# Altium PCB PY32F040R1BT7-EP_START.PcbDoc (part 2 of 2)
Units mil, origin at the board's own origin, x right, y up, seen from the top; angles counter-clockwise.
Board outline 1771.65 x 3925.12 mil, 2 copper layers (Top Layer, Bottom Layer), stack 21 mil thick; 157 components, 167 nets, 618 pads, 288 vias.
Unrouted connection lines stored in the file: 5.

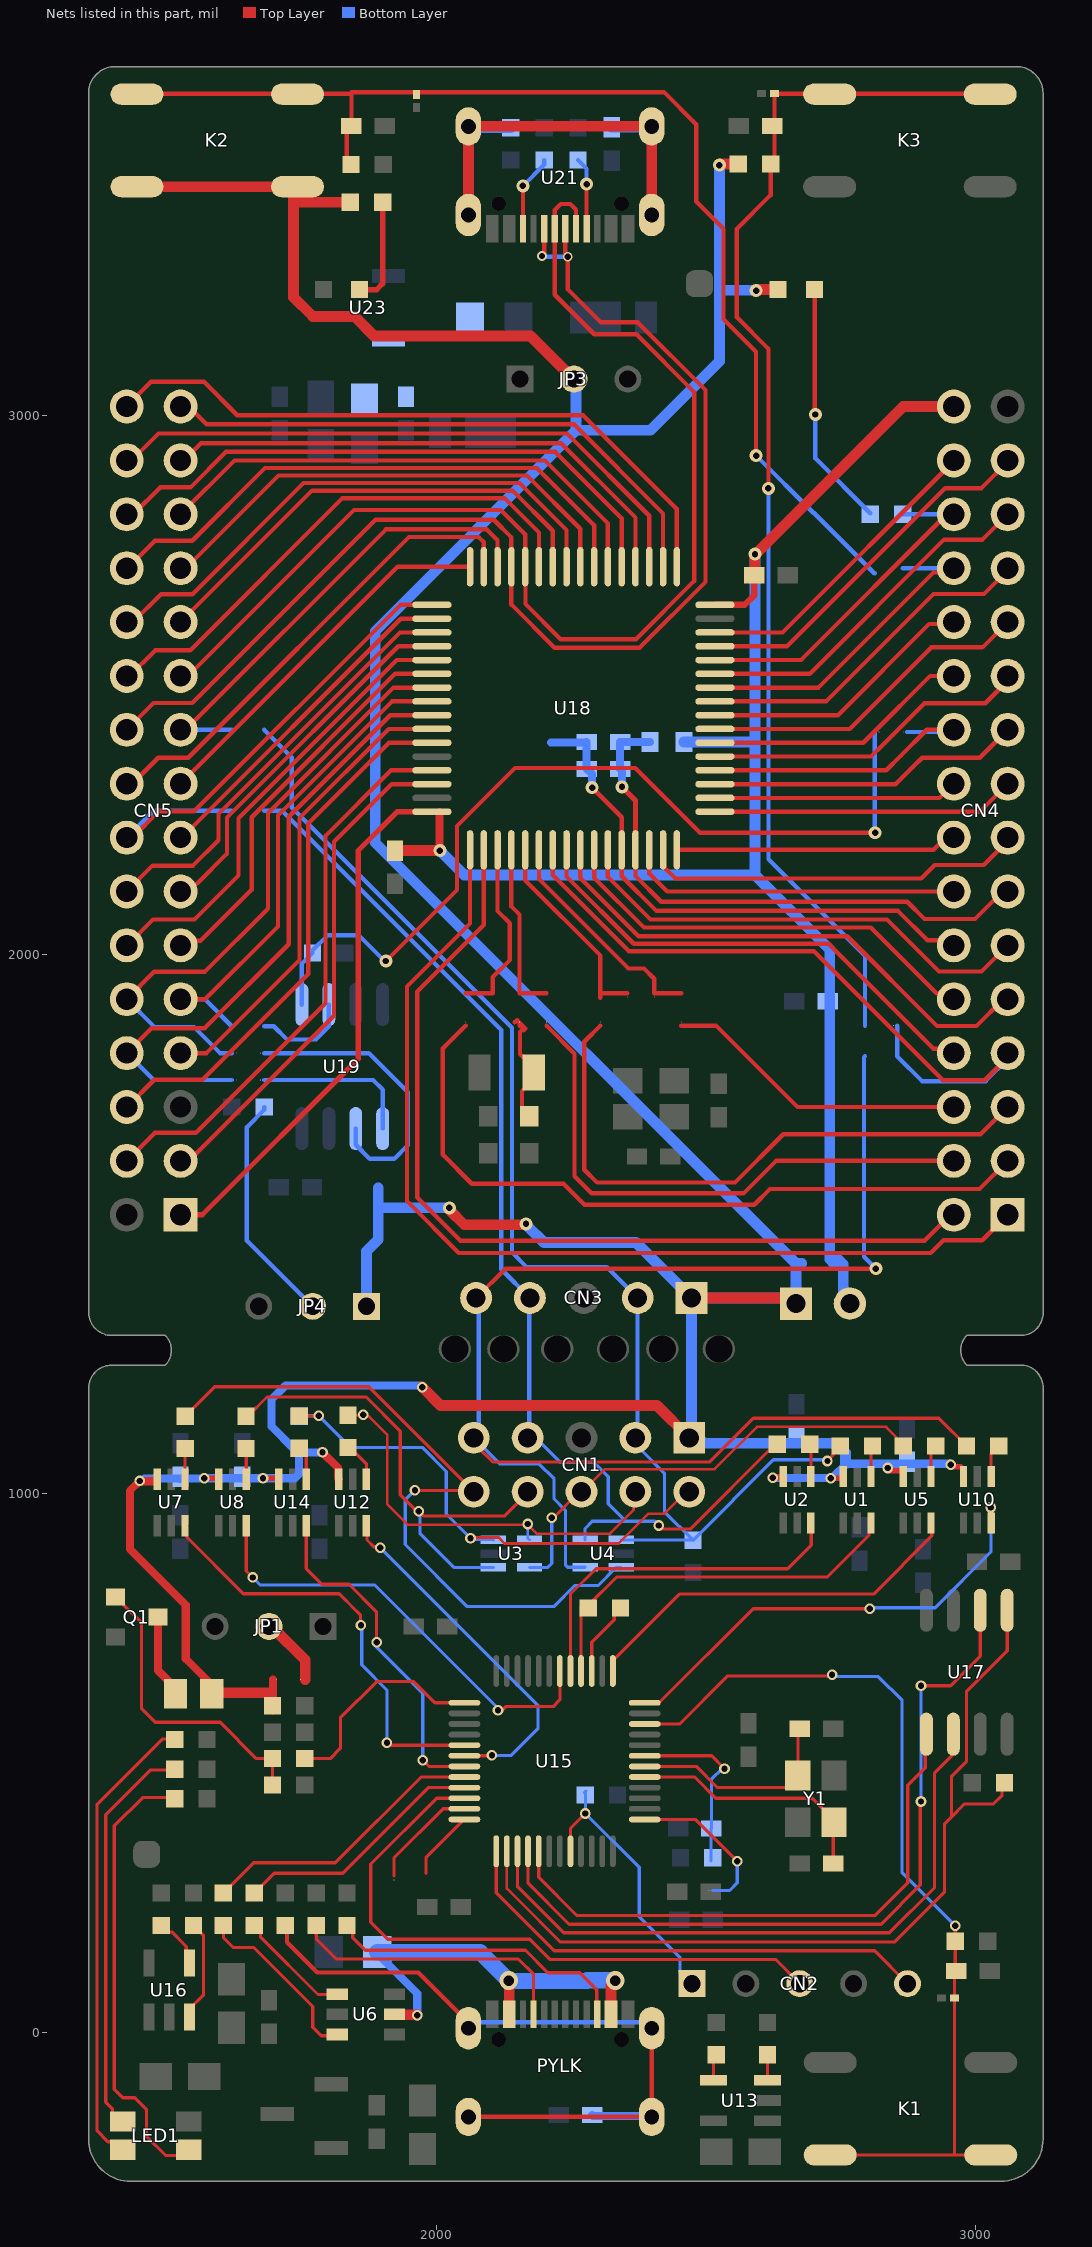
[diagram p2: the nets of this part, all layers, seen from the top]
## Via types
v1: diameter 24, hole 12, Top Layer to Bottom Layer, tented both sides, 117 vias
v2: diameter 19.68, hole 11.81, Top Layer to Bottom Layer, tented both sides, 109 vias
v3: diameter 19.68, hole 11.81, Top Layer to Bottom Layer, 41 vias
v4: diameter 35, hole 20, Top Layer to Bottom Layer, tented both sides, 15 vias
v5: diameter 17.72, hole 11.81, Top Layer to Bottom Layer, tented both sides, 2 vias
v6: diameter 30, hole 15, Top Layer to Bottom Layer, tented both sides, 2 vias
v7: diameter 40, hole 20, Top Layer to Bottom Layer, tented both sides, 2 vias

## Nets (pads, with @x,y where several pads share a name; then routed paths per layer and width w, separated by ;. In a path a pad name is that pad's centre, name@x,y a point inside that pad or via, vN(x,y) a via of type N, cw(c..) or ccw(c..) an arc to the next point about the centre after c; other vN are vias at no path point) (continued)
NetC29_2: C29.2 R43.2 Y3.1 | length 231
  Top Layer w8: 2145.24,1874.18 2149.53,1878.47 ; 2154,1868 2154,1874 2165.2,1862.8 2161.56,1859.16 ; 2161,1866 2161,1862.51 2154.97,1856.48 2154.97,1815.16 2159.65,1810.47 2163.53,1810.47 2171,1803 Y3.1@2171,1775 ; C29.2@2172,1700 2158.5,1713.5 2158.5,1746.51 2180.2,1768.21 Y3.1@2180.2,1781
NetC34_2: C34.2 K3.1 R51.2 R52.1 U20.1 | length 2260.3
  Top Layer w8: v1(2616,2865) 2616,3124.02 2557.01,3183.01 2557.01,3346.47 2620,3409.45 2620,3464.12 R51.2@2620,3467.24 ; R51.2@2623.12,3464.12 2627.3,3468.3 U20.1@2627.3,3598 2627.95,3597.35 3026.9,3597.35 K3.1@3027.55,3596.7
  Bottom Layer w8: v1(2616,2865) 2616,2176.72 2795,1997.72 2795,1868
NetC35_2: C35.2 K2.1 R53.1 R54.2 U22.1 | length 2245.7
  Top Layer w8: K2.1@1444,3596.7 1444.65,3597.35 1842,3597.35 C35.2@1842,3538 ; R54.2@1833.14,3468.87 1833.14,3529.14 C35.2@1842,3538 ; R54.2@1841,3466.26 R54.2@1853,3454.26 ; v1(2593,2926) 2593,3118.54 2532.54,3179 2532.54,3346.86 2481.86,3397.53 2481.86,3540.74 2422.03,3600.57 1842.28,3600.57 1842,3600.29 C35.2@1842,3538
  Bottom Layer w8: v1(2593,2926) 2699.11,2819.89 2700.11,2819.89 2812.39,2707.61 2813,2707.61
NetC38_2: C38.2 C39.2 F2.2 U23.3
NetC40_2: C40.2 PYLK.1 PYLK.2 PYLK.3 PYLK.4 R7.1 | length 1406.9
  Top Layer w8: R7.1@1719,198 1722.29,194.71 1722.29,166.87 1778.64,110.52 1965.97,110.52 2059.12,17.37 PYLK.1@2059.12,7.29 ; PYLK.3@2059.12,-157.27 PYLK.4@2399.28,-157.27 PYLK.2@2399.28,7.29
  Bottom Layer w8: PYLK.1@2070.04,18.21 PYLK.2@2388.36,18.21
  Bottom Layer w15: C40.2@2289,-154 2290.64,-155.64 2397.64,-155.64 PYLK.4@2399.28,-157.27
  Bottom Layer w20: PYLK.1@2059.12,7.29 PYLK.1@2070.04,18.21 ; PYLK.2@2388.36,18.21 PYLK.2@2399.28,7.29
NetC41_2: C41.2 R57.2 U21.1 U21.2 U21.3 U21.4 | length 832
  Top Layer w20: U21.2@2059.12,3372.52 U21.4@2059.12,3537.08 U21.3@2399.28,3537.08 U21.1@2399.28,3372.52 U21.1@2399.28,3380.89
  Bottom Layer w20: U21.4@2059.12,3537.08 2061.7,3534.5 R57.2@2137.5,3534.5 ; C41.2@2325,3535.5 2397.69,3535.5 U21.3@2399.28,3537.08
NetJP4_2: JP4.2 R41.1 | length 433.9
  Bottom Layer w8: R41.1@1680,1717 1680,1711.41 1647.74,1679.15 1647.74,1469.39 JP4.2@1770,1347.13
NetLED1_2: LED1.2 R8.1 | length 846.1
  Top Layer w6: R8.1@1514,433 1511.67,435.33 1454.33,435.33 1402,383 1402,-106 1417.8,-121.8 1439.86,-121.8 1461.53,-143.47 1461.53,-192.84 1497.82,-229.13 1529.08,-229.13 LED1.2@1540.02,-218.18
NetLED1_3: LED1.3 R5.1 | length 884.3
  Top Layer w6: LED1.3@1398.28,-218.48 LED1.3@1412.98,-233.18 ; LED1.3@1417.98,-218.18 1403.28,-203.48 1390.09,-203.48 1370,-183.39 1370,423.34 1490.59,543.93 1513.07,543.93 R5.1@1514,543
NetLED1_4: LED1.4 R4.1 | length 755.1
  Top Layer w6: LED1.4@1410.66,-178.5 1398.36,-166.19 1398.36,-142.26 1386,-129.91 1386,403.34 1469.39,486.73 1512.73,486.73 R4.1@1514,488
NetLED_PB2_2: LED_PB2.2 R46.1 | length 460.1
  Top Layer w8: LED_PB2.2@2701.06,3235.88 2702.06,3234.88 2702.06,3005.95 v1@2703.04,3004.97
  Bottom Layer w8: v1@2703.04,3004.97 2703.04,2920.9 R46.1@2805.06,2818.88
  other v1: 2703.22,3002.23
NetLED_VDD*_1: LED_VDD*.1 R59.1 | length 198.6
  Top Layer w10: LED_VDD*.1@1857,3234 1889,3234 1900,3245 R59.1@1900,3396
NetPYLK_A5: PYLK.A5 R1.2 | length 530.2
  Top Layer w6: R1.2@1776.49,197.99 1776.49,172.82 1813.51,135.79 2151.58,135.79 2180.13,107.25 PYLK.A5@2180.13,33.03
NetPYLK_B5: PYLK.B5 R3.1 | length 566
  Top Layer w6: R3.1@1834,198 1844.31,187.69 1844.31,175.34 1867.85,151.8 2165.11,151.8 2206.66,110.24 2265.55,110.24 2297.17,78.62 2297.17,33.82 PYLK.B5@2298.1,32.89
NetQ1_1: Q1.1 R18.1 R19.2 | length 559
  Top Layer w6: Q1.1@1404,807.8 1405.97,807.8 1417.72,796.06 1417.72,794.23 1452.46,759.49 1452.46,600.34 1477.86,574.94 1598.45,574.94 1665.61,507.78 R18.1@1695.53,507.78 ; R19.2@1695.52,458.88 R18.1@1695.52,507.77
NetQ1_3: Q1.3 R14.1 | length 166.5
  Top Layer w6: Q1.3@1479.49,767.15 Q1.3@1482.74,770.4 ; R14.1@1515.54,628 R14.1@1515.54,633.91
  Top Layer w15: Q1.3@1482.74,770.4 1482.74,671.28 1515.54,638.49 R14.1@1515.54,628
NetR2_1: R2.1 U1.4 | length 57.9
  Top Layer w6: U1.4@2806.23,1031.31 2806.23,1085.02 R2.1@2809.21,1088
NetR6_1: R6.1 U2.4 | length 57.8
  Top Layer w6: R6.1@2692.06,1088 2694.8,1085.27 U2.4@2694.8,1031.31
NetR9_1: R9.1 U5.4 | length 60.3
  Top Layer w6: U5.4@2917.66,1031.31 2917.66,1079.3 R9.1@2926.35,1088
NetR10_1: R10.1 U6.3 | length 332.9
  Top Layer w6: R10.1@1604,198 1604.77,197.23 1604.77,174.69 1622.41,157.05 1660.8,157.05 1770.24,47.61 1770.24,8.87 1785.63,-6.52 1813.74,-6.52 U6.3@1815.53,-4.72
NetR11_1: R11.1 U6.1 | length 227.7
  Top Layer w6: R11.1@1662.75,203 1673.15,192.6 1673.15,176.68 1780,69.83 U6.1@1825.97,69.83
NetR12_1: R12.1 U7.4 | length 59
  Top Layer w6: R12.1@1527.55,1083 1533.14,1077.41 U7.4@1533.14,1026.31
NetR13_1: R13.1 U8.4 | length 60.8
  Top Layer w6: R13.1@1634.94,1083.02 R13.1@1644.82,1073.14 ; U8.4@1646.86,1026.31 R13.1@1646.86,1073.12
NetR17_1: R17.1 U10.4 | length 62.7
  Top Layer w6: U10.4@3029.08,1031.31 3029.08,1073.59 R17.1@3043.49,1088
NetR21_1: R21.1 U12.4 | length 75.3
  Top Layer w6: R21.1@1835.63,1085.11 1839.62,1085.11 1869.71,1055.03 U12.4@1869.71,1026.31
NetR23_2: R23.2 U13.4 | length 49.6
  Top Layer w6: U13.4@2514,-89.5 2514,-47 R23.2@2519,-42
NetR24_2: R24.2 U13.3 | length 47.5
  Top Layer w6: U13.3@2614,-89.5 R24.2@2614,-42
NetR25_1: R25.1 U14.4 | length 62.8
  Top Layer w6: R25.1@1745.2,1083.7 1758.28,1070.62 U14.4@1758.28,1026.31
NetR26_2: R26.2 U15.1 | length 295.4
  Top Layer w6: U15.1@2386.32,394.73 2480.27,394.73 v3(2558,317)
  Bottom Layer w6: 2512.34,262.83 2543.83,262.83 2558,277 v3(2558,317)
NetR28_2: R28.2 U16.4 | length 96.1
  Top Layer w6: R28.2@1489,198 1501,186 1508.44,186 1535.5,158.94 1535.5,134 U16.4@1541.5,128
NetR29_2: R29.2 U16.3 | length 188.5
  Top Layer w6: U16.3@1541.5,28 1541.5,43 1567.56,69.06 1567.56,178.68 1561,185.24 1561,186 R29.2@1549,198
NetR30_1: R30.1 U15.36 | length 129.6
  Top Layer w6: 1980.21,294.75 1980.21,323.26 U15.36@2051.68,394.73
NetR32_1: R32.1 U15.35 | length 201.4
  Top Layer w6: 1920.96,290.4 1920.96,323.38 2012,414.42 U15.35@2051.68,414.42
NetR45_1: R45.1 R47.1 U19.1 | length 1639.5
  Top Layer w8: v1(1906,1988) 2038,2120 2038,2238.69 2145.39,2346.08 2368.77,2346.08 2488.85,2226 v1(2814,2226)
  Bottom Layer w8: U19.1@1750,1907 1750,1983.14 R45.1@1769.57,2002.7 1769.57,2007.76 1797.31,2035.5 1855.88,2035.5 1903.38,1988 v1(1906,1988) ; 2813,2413 2813,2227 v1(2814,2226)
NetR48_1: R48.1 U19.2 | length 180.8
  Bottom Layer w8: 1680,1867 1697.74,1867 1722.33,1842.41 1776.1,1842.41 1800,1866.31 U19.2@1800,1907
NetR49_2: R49.2 U19.6 | length 543.1
  Bottom Layer w8: 1680,1817 1874.09,1817 1946.85,1744.24 1946.85,1646.27 1921.64,1621.07 1875.72,1621.07 1850,1646.79 U19.6@1850,1677
NetR50_2: R50.2 U19.5 | length 299.6
  Bottom Layer w8: 1680,1767 1882.25,1767 1900,1749.25 U19.5@1900,1677
NetR55_1: R55.1 U21.A5 | length 134.2
  Top Layer w8: U21.A5@2278.41,3346.92 v1(2278.41,3429.98)
  Bottom Layer w8: R55.1@2262.5,3474.5 2278.41,3458.59 v1(2278.41,3429.98)
NetR56_2: R56.2 U21.B5 | length 144
  Top Layer w8: U21.B5@2160.3,3346.92 v1(2160.3,3426.54)
  Bottom Layer w8: v1(2160.3,3426.54) 2200,3466.24 R56.2@2200,3474.5
NRST: CN4.7 R39.2 R52.2 U18.7 | length 1383.3
  Top Layer w8: U18.7@2215.61,2194.34 2215.61,2147.39 2357,2006 2700.39,2006 2939.65,1766.75 3017.3,1766.75 3060,1809.45 CN4.7@3060,1817
  Bottom Layer w8: 2855,1868 2855,1811 2901,1765 3019,1765 3060,1806 CN4.7@3060,1817
OSC32_IN: R42.1 R61.1 U18.3 | length 339
  Top Layer w8: 2054,1928 2104,1928 2104,1957.77 2136,1989.77 2136,2058 2113.25,2080.75 U18.3@2113.25,2194.34
OSC32_OUT: R43.1 R62.1 U18.4 | length 322.6
  Top Layer w8: U18.4@2138.84,2194.34 2138.84,2089.16 2154,2074 2154,1928 2204,1928
OSC_IN: R36.2 R63.1 U18.5 | length 382.4
  Top Layer w8: U18.5@2164.43,2194.34 2164.43,2137.57 2304,1998 2304,1928 ; R63.1@2304,1919.75 2304,1928 ; 2354,1928 2304,1928
OSC_OUT: R40.2 R64.1 U18.6 | length 422
  Top Layer w8: U18.6@2190.02,2194.34 2190.02,2139.98 2356,1974 2385.01,1974 2404,1955.01 2404,1928 2454,1928
PA0: CN4.14 U18.14 | length 623.1
  Top Layer w8: U18.14@2394.75,2194.34 2394.75,2150.25 2428,2117 CN4.14@2960,2117
PA1: CN4.15 U18.15 | length 714.9
  Top Layer w8: U18.15@2420.34,2194.34 2420.34,2163.91 2443.25,2141 2899.63,2141 2924.62,2165.99 3015.52,2165.99 3060,2210.47 CN4.15@3060,2217
PA2: CN4.16 U18.16 | length 523.5
  Top Layer w8: U18.16@2445.93,2194.34 2922.45,2194.34 2945.12,2217 CN4.16@2960,2217
PA3: CN4.17 U18.17 | length 564.8
  Top Layer w8: U18.17@2516.66,2265.07 3008.07,2265.07 3012.94,2269.94 CN4.17@3060,2317
PA4: CN4.20 R47.2 U18.20 | length 563
  Top Layer w8: U18.20@2516.66,2341.84 2834.71,2341.84 2861.28,2368.42 2909.86,2417 CN4.20@2960,2417
  Bottom Layer w8: 2873.11,2413.11 2956.11,2413.11 CN4.20@2960,2417
PA5: CN4.21 U18.21 | length 610.6
  Top Layer w8: U18.21@2516.66,2367.43 2806.43,2367.43 2827.1,2388.1 2905.38,2466.38 3018.38,2466.38 3060,2508 CN4.21@3060,2517
PA6: CN4.22 U18.22 | length 494.7
  Top Layer w8: U18.22@2516.66,2393.02 2792.02,2393.02 2806.79,2407.79 2916,2517 CN4.22@2960,2517
PA7: CN4.23 U18.23 | length 625.5
  Top Layer w8: U18.23@2516.66,2418.61 2766.67,2418.61 2918.07,2570.02 3012.98,2570.02 CN4.23@3060,2617
PA8: CN5.24 U18.41 | length 1027.3
  Top Layer w8: CN5.24@1425,2617 1436.86,2617 1488.6,2668.74 1546.74,2668.74 1753,2875 2154,2875 2241.2,2787.8 U18.41@2241.2,2719.66
PA9: CN5.23 U18.42 | length 889.3
  Top Layer w8: CN5.23@1525,2617 1769,2861 2141,2861 2215.61,2786.39 U18.42@2215.61,2719.66
PA10: CN5.22 U18.43 | length 991.5
  Top Layer w8: CN5.22@1425,2517 1430.19,2517 1477.71,2564.52 1542.68,2564.52 1825.16,2847 2126,2847 2190,2783 U18.43@2190.02,2719.66
PA11: CN5.21 U18.44 U21.A7 U21.B7 | length 2225
  Top Layer w8: CN5.21@1525,2517 1538.93,2517 1846.93,2825 2119,2825 2164.43,2779.57 U18.44@2164.43,2719.66 ; U18.44@2165,2719.66 2165,2650.53 2230.29,2585.24 2370.24,2585.24 2478,2693 2478,3044.16 2370.82,3151.34 2292.57,3151.34 2219.36,3224.55 U21.A7@2219.36,3346.92 2219.36,3381.7 2230.63,3392.98 2247.99,3392.98 2258.73,3382.24 U21.B7@2258.73,3346.92
PA12: CN5.20 U18.45 U21.A6 U21.B6 | length 2367.2
  Top Layer w8: CN5.20@1425,2417 1425,2427 1435,2427 1474.77,2466.77 1546.4,2466.77 1886.64,2807 2106,2807 2138.84,2774.16 U18.45@2138.84,2719.66 2138.84,2649.42 2219.02,2569.24 2376.87,2569.24 2499,2691.37 2499,3047.58 2373.38,3173.2 2304.98,3173.2 2243.19,3234.99 v5(2243.19,3295.14) 2239.04,3299.3 U21.A6@2239.04,3346.92 ; v5(2195.65,3296.43) 2199.67,3300.45 U21.B6@2199.67,3346.92
  Bottom Layer w8: v5(2195.65,3296.43) 2197.06,3295.01 2197.2,3295.14 v5(2243.19,3295.14)
PA13: CN5.19 R37.2 U18.46 | length 894.8
  Top Layer w8: CN5.19@1525,2417 1533.86,2417 1905.86,2789 2093,2789 2113.25,2768.75 U18.46@2113.25,2719.66
  Bottom Layer w8: CN5.19@1525,2417 1620,2417
PA14: CN5.16 R38.2 U18.49 | length 961
  Top Layer w8: CN5.16@1425,2217 1436.02,2217 1485.11,2266.09 1550.09,2266.09 1932.93,2648.93 U18.49@1991.34,2648.93
  Bottom Layer w8: CN5.16@1425,2217 1475,2267 1620,2267
PA15: CN5.15 U18.50 | length 634.6
  Top Layer w8: CN5.15@1525,2217 1527.31,2217 1933.65,2623.34 U18.50@1991.34,2623.34
PB0: CN4.26 R53.2 U18.26 | length 630.1
  Top Layer w8: U18.26@2516.66,2495.39 2708.76,2495.39 2922.43,2709.06 2952.06,2709.06 CN4.26@2960,2717
  Bottom Layer w8: 2865,2717 CN4.26@2960,2717
PB1: CN4.27 U18.27 | length 666
  Top Layer w8: U18.27@2516.66,2520.98 2692.83,2520.98 2941.85,2770 3013,2770 CN4.27@3060,2817
PB2: CN4.28 R46.2 U18.28 | length 656.7
  Top Layer w8: U18.28@2516.66,2546.57 2676.57,2546.57 2947,2817 CN4.28@2960,2817
  Bottom Layer w8: R46.2@2865,2817 CN4.28@2960,2817 CN4.28@2955.5,2812.5
PB3: CN5.10 R49.1 U18.55 | length 1146.3
  Top Layer w8: CN5.10@1425,1917 1476.21,1968.21 1570.35,1968.21 1686.97,2084.83 1686.97,2262.25 1920.11,2495.39 U18.55@1991.34,2495.39
  Bottom Layer w8: CN5.10@1425,1917 1476.7,1865.3 1549.73,1865.3 1598.03,1817 1620,1817
PB4: CN5.9 R48.2 U18.56 | length 931.8
  Top Layer w8: CN5.9@1525,1917 1570.49,1917 1705.65,2052.15 1705.65,2258.29 1917.15,2469.8 U18.56@1991.34,2469.8
  Bottom Layer w8: CN5.9@1525,1917 1570,1917 1620,1867
PB5: CN5.8 R50.1 U18.57 | length 1180.4
  Top Layer w8: CN5.8@1425,1817 1471,1863 1569.53,1863 1725.52,2018.99 1725.52,2255.54 1914.19,2444.2 U18.57@1991.34,2444.2
  Bottom Layer w8: CN5.8@1425,1817 1475,1767 1620,1767
PB6: CN5.7 U18.58 | length 869.9
  Top Layer w8: CN5.7@1525,1817 1573.07,1817 1745.71,1989.65 1745.71,2253.1 1911.22,2418.61 U18.58@1991.34,2418.61
PB7: CN5.6 U18.59 | length 1010
  Top Layer w8: CN5.6@1425,1717 1425.62,1717 1476.12,1767.5 1565.36,1767.5 1761.71,1963.85 1761.71,2243.2 1911.54,2393.02 U18.59@1991.34,2393.02
PB8: CN5.4 U18.61 | length 1048.5
  Top Layer w8: CN5.4@1425,1617 1477,1669 1553.03,1669 1793.71,1909.68 1793.71,2220.2 1915.36,2341.84 U18.61@1991.34,2341.84
PB9: CN5.3 U18.62 | length 945
  Top Layer w8: CN5.3@1525,1617 1539.88,1617 1555.02,1632.14 1555.38,1632.14 1809.71,1886.47 1809.71,2209.14 1916.83,2316.25 U18.62@1991.34,2316.25
PB10: CN4.29 U18.29 | length 687.8
  Top Layer w8: U18.29@2516.66,2572.16 2650.52,2572.16 2943.92,2865.56 3011.32,2865.56 3060,2914.24 CN4.29@3060,2917
PB11: CN4.30 U18.30 | length 576.4
  Top Layer w8: U18.30@2516.66,2597.75 2642.17,2597.75 2960,2915.58 CN4.30@2960,2917
PB12: CN5.32 U18.33 | length 1245.7
  Top Layer w8: CN5.32@1425,3017 1425,3018.08 1469.85,3062.93 1568.24,3062.93 1630.17,3001 2272,3001 2445.93,2827.07 U18.33@2445.93,2719.66
PB13: CN5.31 U18.34 | length 1076.5
  Top Layer w8: CN5.31@1525,3017 1539.88,3017 1572.88,2984 2255,2984 2420.34,2818.66 U18.34@2420.34,2719.66
PB14: CN5.30 U18.35 | length 1148.3
  Top Layer w8: CN5.30@1425,2917 1433.75,2917 1483.75,2967 2242,2967 2394.75,2814.25 U18.35@2394.75,2719.66
PB15: CN5.29 U18.36 | length 1008.2
  Top Layer w8: CN5.29@1525,2917 1527.82,2914.18 1562.64,2949 2231,2949 2369.16,2810.84 U18.36@2369.16,2719.66
PC0: CN4.8 U18.8 | length 904.1
  Top Layer w8: U18.8@2241.2,2194.34 2241.2,2144.8 2366,2020 2727.38,2020 2922.44,1824.95 2952.05,1824.95 CN4.8@2960,1817
PC1: CN4.9 U18.9 | length 979.7
  Top Layer w8: U18.9@2266.8,2194.34 2266.8,2142.2 2375,2034 2762.11,2034 2928.7,1867.41 3002.03,1867.41 3051.62,1917 CN4.9@3060,1917
PC2: CN4.10 U18.10 | length 812.8
  Top Layer w8: U18.10@2292.39,2194.34 2292.39,2142.61 2385,2050 2805.66,2050 2928.14,1927.52 2949.48,1927.52 CN4.10@2960,1917
PC3: CN4.11 U18.11 | length 885.2
  Top Layer w8: U18.11@2317.98,2194.34 2317.98,2144.02 2397,2065 2835.95,2065 2932.58,1968.37 3011.37,1968.37 CN4.11@3060,2017
PC4: CN4.24 U18.24 | length 514.9
  Top Layer w8: U18.24@2516.66,2444.2 2744.81,2444.2 2914.11,2613.5 2956.5,2613.5 CN4.24@2960,2617
PC5: CN4.25 U18.25 | length 648.1
  Top Layer w8: U18.25@2516.66,2469.8 2722.95,2469.8 2922.26,2669.11 3016.12,2669.11 3060,2712.99 CN4.25@3060,2717
PC6: CN5.28 U18.37 | length 1107.6
  Top Layer w8: CN5.28@1425,2817 1437.04,2817 1486.99,2866.94 1543.24,2866.94 1609.3,2933 2220,2933 2343.57,2809.43 U18.37@2343.57,2719.66
PC7: CN5.27 U18.38 | length 963.2
  Top Layer w8: CN5.27@1525,2817 1625,2917 2201,2917 2317.98,2800.02 U18.38@2317.98,2719.66
PC8: CN5.26 U18.39 | length 1065.4
  Top Layer w8: CN5.26@1425,2717 1426.2,2717 1477.22,2768.03 1546.55,2768.03 1681.53,2903 2186,2903 2292.39,2796.61 U18.39@2292.39,2719.66
PC9: CN5.25 U18.40 | length 924.5
  Top Layer w8: CN5.25@1525,2717 1529.91,2721.91 1539.76,2721.91 1706.86,2889 2168,2889 2266.8,2790.2 U18.40@2266.8,2719.66
PC10: CN5.14 U18.51 | length 794
  Top Layer w8: CN5.14@1425,2117 1473,2165 1547.93,2165 1595.1,2212.17 1595.1,2260.88 1931.97,2597.75 U18.51@1991.34,2597.75
PC11: CN5.13 U18.52 | length 694.1
  Top Layer w8: CN5.13@1525,2117 1539.88,2117 1554.69,2131.81 1555.7,2131.81 1611.1,2187.21 1611.1,2254.25 1929,2572.16 U18.52@1991.34,2572.16
PC12: CN5.12 U18.53 | length 847.8
  Top Layer w8: CN5.12@1425,2017 1425.95,2017 1473.95,2065 1550.57,2065 1632.48,2146.91 1632.48,2253 1926.04,2546.57 U18.53@1991.34,2546.57
PC13: CN4.2 U18.2 | length 1745.7
  Top Layer w8: U18.2@2087.66,2194.34 2087.66,2054.85 1964,1931.19 1964,1549.22 2044.54,1468.67 2905.74,1468.67 2954.07,1517 CN4.2@2960,1517
PC14: CN4.3 R61.2 | length 1377.8
  Top Layer w8: 2054,1868 2011.47,1825.47 2011.47,1628.57 2065.35,1574.7 2235.53,1574.7 2274.57,1535.66 2589.66,1535.66 2618.65,1564.65 3007.65,1564.65 CN4.3@3060,1617
PC15: CN4.4 R62.2 | length 1043.1
  Top Layer w8: 2204,1868 2256,1816 2256,1588.65 2287.93,1556.73 2569.73,1556.73 2630,1617 CN4.4@2960,1617
PF0: CN4.5 R63.2 | length 1133.5
  Top Layer w8: 2304,1868 2274.14,1838.14 2274.14,1600.64 2297.93,1576.85 2553.85,1576.85 2643.46,1666.46 3009.46,1666.46 CN4.5@3060,1717
PF1: CN4.6 R64.2 | length 568.5
  Top Layer w8: 2454,1868 2518.75,1868 2669.75,1717 CN4.6@2960,1717
PF3: CN4.18 U18.18 | length 454.2
  Top Layer w8: U18.18@2516.66,2290.66 2933.18,2290.66 2959.52,2317 CN4.18@2960,2317
PF4: CN4.19 U18.19 | length 585.1
  Top Layer w8: U18.19@2516.66,2316.25 2852.38,2316.25 2884.86,2348.73 2901.33,2365.2 3008.2,2365.2 CN4.19@3060,2417
PF5: CN5.18 U18.47 | length 902
  Top Layer w8: CN5.18@1425,2317 1435.31,2317 1483.57,2365.26 1539.18,2365.26 1948.92,2775 2078,2775 2087.66,2765.34 U18.47@2087.66,2719.66
PF6: CN5.17 U18.48 | length 703.9
  Top Layer w8: CN5.17@1525,2317 1927.66,2719.66 U18.48@2062.07,2719.66
PF7: CN5.11 U18.54 | length 753.8
  Top Layer w8: CN5.11@1525,2017 1533.5,2025.5 1562.02,2025.5 1657.02,2120.5 1657.02,2254.91 1923.08,2520.98 U18.54@1991.34,2520.98
PF9: CN4.1 U18.1 | length 1884.7
  Top Layer w8: U18.1@2062.07,2194.34 2062,2194.26 2062,2057.54 1945,1940.54 1945,1542.34 2041.27,1446.07 2917.27,1446.07 2940.92,1469.73 3012.73,1469.73 CN4.1@3060,1517
PYLK_BOOT0: CN2.1 R27.1 U15.44 | length 522.7
  Top Layer w6: U15.44@2248.53,335.68 2248.53,378.07 v2(2276.21,405.75)
  Bottom Layer w6: R27.1@2277.26,447.4 2274.49,444.63 2276.21,442.9 v2(2276.21,405.75) 2376,305.96 2376,214 2451.96,138.04 2451.96,112.04 CN2.1@2474,90
PYLK_KEY: C5.2 K1.2 R15.1 U11.1 U15.10 | length 1779.6
  Top Layer w6: U15.10@2386.32,571.9 2451.14,571.9 2540.44,661.2 2732.2,661.2 v2(2734,663) ; K1.2@2730.55,-228 2992.3,-228 3007.51,-228 K1.2@2993.02,-242.49 ; C5.2@2961.3,110.7 U11.1@2961.3,63 2961.3,-228 K1.2@3028.55,-228 ; v2(2962.39,197.54) 2962.76,197.17 R15.1@2962.76,168.85 C5.2@2962.76,115.49
  Bottom Layer w6: v2(2734,663) 2737.06,659.94 2746.62,659.94 2746.69,659.88 2819.92,659.88 2864,615.8 2864,295.93 v2(2962.39,197.54)
PYLK_NRST: C23.2 R35.1 U15.7 | length 341.9
  Top Layer w6: U15.7@2386.32,512.84 2510.36,512.84 v2(2534.4,488.8)
  Bottom Layer w6: R35.1@2509.12,318 2509.12,377 C23.2@2510.12,378 2510.12,469 2529.92,488.8 v2(2534.4,488.8)
PYLK_OSCIN: C18.2 U15.5 Y1.3 | length 465.6
  Top Layer w6: U15.5@2386.32,473.47 2479.05,473.47 2518.42,434.1 2697.11,434.1 2737.59,393.63 Y1.3@2737.59,389.69 2736.12,388.22 C18.2@2736.12,313
PYLK_OSCOUT: C24.2 U15.6 Y1.1 | length 399.8
  Top Layer w6: U15.6@2386.32,493.16 2481.99,493.16 2521.36,453.79 2651.03,453.79 2670.66,473.41 Y1.1@2670.66,476.31 2670.66,559.54 C24.2@2674.12,563
PYLK_SPI_CS: R34.1 U15.38 U17.1 | length 1667.6
  Top Layer w5: U15.38@2130.42,335.68 2130.42,266.62 2191.66,205.38
  Top Layer w6: 2191.66,205.38 2229.95,167.09 2849.51,167.09 2942.88,260.47 2942.88,386.88 2955.77,399.77 ; R34.1@3054,463 3049.62,458.62 3049.62,439.69 3033.36,423.42 2979.42,423.42 2955.77,399.77 ; U17.1@3059,783 3059,708 2983.69,632.69 2983.69,503.01 2955.77,475.09 2955.77,399.77
PYLK_SPI_MISO: U15.40 U17.2 | length 1437.2
  Top Layer w6: U15.40@2169.79,335.68 2169.79,276.3 2245.8,200.3 2825,200.3 2897.9,273.2 2897.9,426.9 v2(2899,428) ; v2(2899,643) 2954,643 3009,698 U17.2@3009,783
  Bottom Layer w6: v2(2899,428) v2(2899,643)
PYLK_SPI_MOSI: U15.41 U17.5 | length 1077.9
  Top Layer w6: U15.41@2189.47,335.68 2189.47,287.49 2260.66,216.3 2813.42,216.3 2874.53,277.41 2874.53,458.09 2907.13,490.69 2907.13,551.13 U17.5@2909,553
PYLK_SPI_SCK: U15.39 U17.6 | length 1208.9
  Top Layer w6: U15.39@2150.1,335.68 2150.1,270.36 2210.32,210.14 2236.17,184.3 2840.07,184.3 2924.21,268.44 2924.21,481.06 2955.94,512.79 2955.94,549.94 U17.6@2959,553
SWD_SCK: CN2.5 U15.37 | length 910.1
  Top Layer w6: U15.37@2110.73,335.68 2110.73,258.75 2218.48,151 2813,151 CN2.5@2874,90
SWD_SDA: CN2.3 U15.34 | length 1175.6
  Top Layer w6: U15.34@2051.68,434.1 2000.11,434.1 1878.05,312.04 1878.05,203.71 1909.57,172.2 2172.75,172.2 2209.95,135 2629,135 CN2.3@2674,90
T_RESET: CN1.9 CN3.5 R17.2 R39.1 U4.4 | length 2794
  Top Layer w6: CN1.9@2076.78,1085.78 2104.2,1058.36 2506.91,1058.36 2587.99,1139.44 2932.06,1139.44 R17.2@2983.49,1088
  Top Layer w8: CN3.5@2073.26,1362.56 2127.65,1416.95 v1(2815.47,1416.95)
  Bottom Layer w6: CN1.9@2069,1103 2117.22,1054.78 2190.02,1054.78 2218.1,1026.69 2218.1,989.42 2239.15,968.37 2239.15,867.31 2243.61,862.85 2275.09,862.85 U4.4@2275.54,862.41
  Bottom Layer w8: CN1.9@2069,1103 2078.04,1112.04 2078.04,1357.78 CN3.5@2073.26,1362.56 ; 2795,1811 2793.46,1809.46 2793.46,1438.96 v1(2815.47,1416.95)
T_RESETa: U10.3 U15.12 | length 870.1
  Top Layer w6: U15.12@2386.32,611.27 2412.79,611.27 2587.47,785.96 2675.53,785.96 v2(2803.91,785.96) ; v2(3028.82,973.7) 3029.08,973.44 U10.3@3029.08,944.69
  Bottom Layer w6: v2(2803.91,785.96) 2805.65,787.7 2925.4,787.7 3028.82,891.11 v2(3028.82,973.7)
T_RTCK_DTRa: U5.3 U15.13 | length 731.2
  Top Layer w6: U15.13@2327.27,670.32 2327.27,689.57 2450.7,813 2810.99,813 2919.18,921.19 2919.18,943.16 U5.3@2917.66,944.69
T_RTCK_VCP_DTR: CN1.6 R9.2 U3.5 | length 868.3
  Top Layer w5: v2(2213.81,954.67) 2217.24,954.67 2265.57,1003 CN1.6@2269,1003 2270.63,1003 2312.49,1044.86 2515.73,1044.86 2594.3,1123.44 2833.98,1123.44 2854.35,1103.07 2854.35,1100 R9.2@2866.35,1088
  Bottom Layer w6: U3.5@2172.46,862.41 2206.51,862.41 2213.81,869.71 v2(2213.81,954.67)
T_TCK_SWCLK: CN1.7 CN3.4 R6.2 R38.1 U4.5 | length 2115.5
  Top Layer w6: CN1.7@2174,1113 CN1.7@2175.35,1114.35 ; v2(2412.5,940.32) 2419.14,933.69 2470.96,933.69 2625.28,1088 R6.2@2632.06,1088
  Bottom Layer w6: CN1.7@2176.5,1110.5 2229.47,1057.53 2291.65,1057.53 2318.6,1030.57 2318.6,980.54 2351.14,948 ; U4.5@2275.54,913.59 2275.54,934.54 2289,948 2351.14,948 ; v2(2412.5,940.32) 2404.82,948 2351.14,948
  Bottom Layer w8: 1680,2267 1713,2267 2119.97,1860.03 2119.97,1415.86 CN3.4@2173.26,1362.56 2171.79,1361.1 2171.79,1105.79 CN1.7@2169,1103
T_TCK_SWCLKa: U2.3 U15.17 | length 668.1
  Top Layer w5: U15.17@2248.53,670.32 2248.53,812.76 2295.77,860
  Top Layer w6: 2295.77,860 2401.62,860 2651.43,860 2695.41,903.98 2695.41,944.08 U2.3@2694.8,944.69
T_TDI_VCP_TX: CN1.4 R21.2 U3.4 | length 783.1
  Top Layer w5: R21.2@1835.63,1145.11 1871.9,1145.11 1908.54,1108.48 1908.54,979.62 1946.29,941.86 v2@2169,941.86 ; R21.2@1835.63,1148.11 R21.2@1837.13,1146.61 ; v2@2169.02,941.86 2185.78,925.11 2321.76,925.11 2365.56,968.9 2365.56,999.56 CN1.4@2369,1003
  Bottom Layer w5: v2@2169.06,942.94 2169.06,917 U3.4@2172.46,913.59
  other v2: 2169,943
  other v3: 1863.96,1145.98
T_TDI_VCP_TXa: U12.3 U15.30 | length 672
  Top Layer w6: U12.3@1869.71,939.69 1870.93,938.47 1870.93,913.37 1883.24,901.06 1893.56,901.06 v2(1895.31,899.31) ; U15.30@2051.68,512.84 2102.02,512.84 v2(2102.76,513.58)
  Bottom Layer w6: v2(1895.31,899.31) 2188.09,606.53 2188.09,562.77 2154.71,529.38 2138.91,513.58 v2(2102.76,513.58)
T_TDO_SWO: CN1.10 R12.2 U4.3 | length 1333.3
  Top Layer w6: R12.2@1533.66,1143.08 1588.47,1197.9 1874.1,1197.9 CN1.10@2062.51,1009.49 ; v2(1959.87,1005.75) 1960.54,1005.08 2058.1,1005.08 CN1.10@2062.51,1009.49 ; CN1.10@2069,1003 CN1.10@2062.51,1009.49
  Bottom Layer w6: v2(1959.87,1005.75) 1941.83,987.72 1941.83,905.08 2057.06,789.86 2217.29,789.86 2256.42,828.99 2300.45,828.99 2333.88,862.41 U4.3@2342.46,862.41 U4.3@2340.15,860.1
T_TDO_SWOa: U7.3 U15.29 | length 807.7
  Top Layer w6: U7.3@1533.14,939.69 1533.14,921.86 1641.46,813.54 1819.08,813.54 1825.63,807 1826.01,807 1843,790.01 1843,789.63 1858.93,773.7 1858.93,755.69 v2(1859.62,755) ; v2(1907.88,537.33) 1912.68,532.53 1995.55,532.53 U15.29@2051.68,532.53
  Bottom Layer w6: v2(1859.62,755) 1860.95,753.68 1860.95,681.93 1907.88,635 v2(1907.88,537.33)
T_TMS_SWDIO: CN1.3 CN3.2 R2.2 R37.1 R65.2 U4.1 | length 2390.3
  Top Layer w6: CN1.3@2373.37,1089.19 CN1.3@2379.56,1083 ; v2@2725.62,1061.31 2736.21,1071.9 2736.21,1075 R2.2@2749.21,1088
  Bottom Layer w6: U4.1@2342.77,913.29 R65.2@2475.29,913.29 ; CN1.3@2377.59,1082.7 2422.86,1037.42 2422.86,966.14 R65.2@2476,913 2625.25,1062.25 2723.25,1062.25 v2(2725.43,1060.07)
  Bottom Layer w8: 1680,2417 1731.3,2365.7 1731.3,2272.7 2139.84,1864.16 2139.84,1447.46 2167.16,1420.15 2315.67,1420.15 CN3.2@2373.26,1362.56 2373,1362.3 2373,1107 CN1.3@2369,1103
T_TMS_SWDIOa: R31.1 U1.3 U15.16 | length 723.8
  Top Layer w6: U15.16@2268.21,670.32 R31.1@2268.21,790.37 ; R31.1@2281.46,787.37 2281.46,791.99 2334.12,844.65 2390.7,844.65 2725.22,844.65 2802.34,921.77 2802.34,940.8 U1.3@2806.23,944.69
T_TMS_SWDIOa_IN: R31.2 U15.15 | length 143.2
  Top Layer w6: U15.15@2287.9,670.32 2287.9,723.64 2329.82,765.56 R31.2@2329.82,796.16
T_TRST_RTSa: U8.3 U15.18 | length 840.3
  Top Layer w6: U8.3@1646.86,939.69 1646.86,855.86 v2(1658.82,843.9) ; v2(2113.92,597.35) 2117.83,593.44 2128.54,604.16 2216.39,604.16 2228.84,616.6 U15.18@2228.84,670.32
  Bottom Layer w6: v2(1658.82,843.9) 1672.81,829.91 1885.65,829.91 2113.92,601.64 v2(2113.92,597.35)
T_TRST_VCP_RTS: CN1.8 R13.2 U3.1 | length 935
  Top Layer w6: R13.2@1646.3,1143.1 1649.54,1143.1 1685.24,1178.8 1869.25,1178.8 1932.58,1115.47 1932.58,997.56 1963.4,966.73 v2(1966.86,966.73) 1975.6,958 2126.67,958 2174,1005.33 CN1.8@2174,1013
  Bottom Layer w6: v2(1966.86,966.73) 1969,964.6 1969,925.6 2032.19,862.41 U3.1@2105.54,862.41
T_VCP_RX: CN1.2 R22.1 R25.2 U3.3 | length 1000.9
  Top Layer w5: v2(2062.97,916.74) 2064.23,918 2115.42,918 2126.45,906.97 2337.91,906.97 2393.3,962.36 2423.36,962.36 CN1.2@2474,1013
  Top Layer w6: R25.2@1745.2,1143.7 1780.7,1143.7 v3(1781,1144) ; R25.2@1745.2,1154.85 R25.2@1745.32,1154.97
  Bottom Layer w6: R22.1@1745,1143 1746,1144 v3(1781,1144) 1839.72,1085.28 1973.26,1085.28 2018.05,1040.5 2018.05,961.66 v2(2062.97,916.74) 2062.23,916 2062.23,914.77 2104.36,914.77 U3.3@2105.54,913.59
T_VCP_RXa: U14.3 U15.31 | length 636
  Top Layer w6: U14.3@1758.28,939.69 1758.28,860.29 1787.27,831.3 1837.54,831.3 1888.4,780.43 1888.4,724.38 v2(1889,723.78) ; v2(1974.4,504.75) 1985.99,493.16 U15.31@2051.68,493.16
  Bottom Layer w6: v2(1889,723.78) 1889,714.42 1974.4,629.02 v2(1974.4,504.75)
TVDD: C11.2 C12.2 C13.2 C14.2 CN1.1 CN3.1 JP2.1 JP3.2 JP4.1 K2.2 LED_PB2.1 R14.2 R16.2 R22.2 R33.2 R44.1 R51.1 R58.1 R59.2 U1.6 U2.6 U5.6 U7.6 U8.6 U10.6 U12.6 U14.6 | length 8669.2
  Top Layer w6: U8.6@1595.67,1026.31 U8.6@1598.56,1029.2 ; U14.6@1707.1,1026.31 U14.6@1709.99,1029.2
  Top Layer w10: v2(1569,1028) 1593.98,1028 U8.6@1595.67,1026.31 ; v3@1679,1028 1705.41,1028 U14.6@1707.1,1026.31 ; v3(2731.88,1028.09) 2753.07,1028.09 2753.16,1028 2755.05,1029.89 U1.6@2755.05,1031.31 ; v2(2837.29,1047.06) 2842.61,1041.74 2866.47,1041.74 U5.6@2866.47,1031.31 ; v2@2962.68,1049.1 2972.91,1049.1 2977.9,1044.1 U10.6@2977.9,1031.31
  Top Layer w12: v2@2624.9,1029.9 U2.6@2643.01,1029.9
  Top Layer w15: v2(1449,1023) 1430.66,1004.66 1430.66,896.6 1534.53,792.73 1534.53,692.95 1574.52,652.96 1574.52,635.95 R14.2@1582.46,628 R14.2@1584.24,629.78 ; v2@1449.63,1022.37 U7.6@1481.35,1022.37 ; 1692.07,629.78 1696.08,625.77 ; R16.2@1696.08,597.02 1696.08,625.77 ; 1696.08,654.52 1696.08,625.77 ; v3(1788.28,1076.05) 1816.84,1047.49 1816.84,1028 U12.6@1818.53,1026.31 ; v2(2624,1029) v2@2624.9,1029.9
  Top Layer w20: K2.2@1444,3425 K2.2@1737.32,3425 ; R14.2@1584.24,629.78 1692.07,629.78 ; K2.2@1742,3425 1734.49,3417.49 1734.49,3392 ; R59.2@1840,3396 1738.49,3396 1734.49,3392 ; v3(1973.35,1197.16) 2007.41,1163.1 2408.9,1163.1 CN1.1@2469,1103 ; v1(2023.87,1529.85) 2023.87,1525.91 2051.44,1498.34 2161.51,1498.34 2162.41,1499.23 v1@2164.15,1499.23 ; JP3.2@2254.27,3068 2174.38,3147.9 1884.03,3147.9 1847.55,3184.38 1770.04,3184.38 1734.49,3219.93 1734.49,3392 ; CN3.1@2473.26,1362.56 2656.56,1362.56 JP2.1@2667,1352.13 ; v1(2525,3465) 2527.24,3467.24 R51.1@2560,3467.24 ; v1(2593,3232) 2595,3234 LED_PB2.1@2634,3234
  Bottom Layer w15: v2(1449,1023) 1452.79,1023 1457.67,1027.88 C14.2@1522.87,1027.88 ; C14.2@1524,1026.74 C14.2@1522.87,1027.88 ; v2@1568.88,1027.88 C14.2@1522.87,1027.88 ; v2(1569,1028) v3(1677.77,1028) 1737,1028 1745,1036 R22.2@1745,1076.05 ; v3(1788.28,1076.05) R22.2@1745,1076.05 ; v3(1973.35,1197.16) 1970.13,1200.38 1719.38,1200.38 1694,1175 1694,1123.76 1734.76,1083 R22.2@1745,1083 R22.2@1745,1076.05 ; v2@2624.38,1028.62 v3@2731.36,1028.62 ; v3(2731.88,1028.09) 2733.15,1028.09 2735.49,1030.43 2736.09,1030.43 2760.58,1054.92 ; 2758.72,1054.92 2760.58,1054.92 ; v2(2954,1053) 2952.08,1054.92 2760.58,1054.92
  Bottom Layer w20: JP4.1@1870,1347.13 1870,1449.46 1891.72,1471.17 1891.72,1530.04 ; 1891.72,1566.57 1891.72,1530.04 ; v1(2023.87,1529.85) 1891.91,1529.85 1891.72,1530.04 ; v1@2166.77,1498.15 2168,1496.92 2168,1496.8 2199.3,1465.5 2370.32,1465.5 CN3.1@2473.26,1362.56 2656.56,1362.56 JP2.1@2667,1352.13 2667,1426.61 ; JP3.2@2255,3068 2258.91,3064.09 2258.91,2972.91 ; CN1.1@2472.94,1106.94 CN3.1@2472.94,1362.24 ; CN1.1@2476.04,1111.26 2497.46,1093 2740.9,1093 2758.72,1075.18 2758.72,1054.92 ; v1(2525,3465) 2525,3233 ; v1@2593,3233 2525,3233 ; 2677.64,1426.61 2667,1426.61 ; 2258.91,2972.91 2396.91,2972.91 2525,3101 2525,3233 ; 2258.91,2972.91 1886.02,2600.02 1886.02,2207.59 2667,1426.61
  other v1: 2166,1500
TVDD*: JP1.2 R33.1 | length 129
  Top Layer w20: JP1.2@1689,753 1693.73,753 1756.08,690.65 1756.08,654.52
TVDD_DISCHARGE_EN: R18.2 U15.25 | length 404.9
  Top Layer w6: R18.2@1755.53,507.78 1802.51,507.78 1821.48,526.75 1821.48,583.55 1888.58,650.66 1957.61,650.66 1997,611.27 U15.25@2051.68,611.27
USB_DM: R10.2 U15.32 | length 536.9
  Top Layer w6: R10.2@1604,258 1660.4,314.4 1812.28,314.4 1971.36,473.47 U15.32@2051.68,473.47
USB_DP: R11.2 U15.33 | length 471.3
  Top Layer w6: R11.2@1661.5,258 1698.45,294.95 1825.73,294.95 1984.56,453.79 U15.33@2051.68,453.79
VBUS_PYLK: F1.1 PYLK.A4 PYLK.A9 PYLK.B4 PYLK.B9 U6.5 | length 755
  Top Layer w10: PYLK.A4@2128.81,32.89 PYLK.B9@2140.62,32.89 ; PYLK.B4@2317.78,32.88 PYLK.A9@2329.6,32.88
  Top Layer w20: U6.5@1922.15,33 1922.98,32.17 1963.58,32.17 v2(1964.2,31.55) ; PYLK.B9@2135.05,50.56 v4@2135.05,94.45 ; PYLK.A9@2323.87,52.86 v4@2323.87,86.67
  Bottom Layer w15: F1.1@1889.98,149 1889.98,148.39 1889.98,145.75 1964.2,71.53 v2(1964.2,31.55)
  Bottom Layer w20: v4@2331.13,95.01 v4(2331.62,95.5)
  Bottom Layer w30: F1.1@1889.98,148.39 2081.11,148.39 v4(2134,95.5) ; v4@2134.49,95.01 2279.68,95.01 ; 2279.68,96.41 v4@2330.72,96.41
VCCA: C30.2 C42.1 CN4.13 L1.2 U18.13 | length 1061.5
  Top Layer w8: U18.13@2369.16,2194.34 2369.16,2145.84 2417,2098 2873.72,2098 2905.71,2066.01 2999.14,2066.01 3050.14,2117 CN4.13@3060,2117
  Top Layer w10: v1(2344.18,2311.23) 2369.16,2286.25 U18.13@2369.16,2194.34
  Bottom Layer w15: v1(2344.18,2311.23) 2344.18,2341.35 C30.2@2340.94,2344.58 2340.51,2345.01 C42.1@2340.51,2394.65 2340.63,2394.53 L1.2@2396.29,2394.53
VDD: C26.1 C32.2 C33.2 CN4.32 CN5.1 JP2.2 L1.1 R58.2 U18.32 U18.64 | length 4011.7
  Top Layer w10: CN5.1@1525,1517 1565.14,1517 1854.55,1806.41 1854.55,2192.55 1927.07,2265.07 2004.69,2265.07 U18.64@2005.66,2264.1 ; v1@2005.33,2193 v1@2005.66,2193.34
  Top Layer w12: U18.32@2516.66,2648.93 2571.93,2648.93 2590,2667 C26.1@2590,2704
  Top Layer w15: v1@2005.66,2193.34 U18.64@2005.66,2264.1
  Top Layer w20: C32.2@1923,2193 v1@2005.33,2193 ; C26.1@2590,2704 2590.5,2704.5 2590.5,2742.5 v1(2591,2743) ; v1@2593.12,2744.12 2866,3017 CN4.32@2960,3017
  Bottom Layer w20: v1(2006,2193) 2051.26,2147.74 2591,2147.74 ; L1.1@2459.28,2394.53 2591,2394.53 ; v1(2591,2743) 2591,2394.53 ; 2737.64,1426.61 2729.62,1434.62 2729.62,2009.12 2591,2147.74 ; 2745.52,1434.48 2754.76,1425.24 2754.76,1375.19 2767,1362.95 JP2.2@2767,1352.13 ; 2591,2147.74 2591,2394.53
VSSA: C30.1 C42.2 CN4.12 R60.1 U18.12 | length 1012.3
  Top Layer w8: v1(2288.81,2309.61) 2343.57,2254.86 U18.12@2343.57,2194.34 2343.57,2145.43 2408,2081 2856.38,2081 2910.68,2026.7 2950.3,2026.7 CN4.12@2960,2017
  Bottom Layer w15: 2212.63,2393.15 2277.01,2393.15 C42.2@2278.51,2394.65 2278.51,2345.01 C30.1@2278.94,2344.58 2288.81,2334.71 v1(2288.81,2309.61)
pads on no net: PYLK. PYLK.A8 PYLK.B8 U15.42 U15.45 U21. U21.A8 U21.B8

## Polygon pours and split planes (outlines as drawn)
GND on Top Layer "NONET_L-01_P-001" (solid, remove dead copper, pour order 4): 1359.13,3648.12 3124,3648.12 3124,-277 1350.51,-277
GND on Bottom Layer "NONET_L-01_P-001" (solid, remove dead copper, pour order 3): 1359.13,3648.12 3124,3648.12 3124,-277 1350.51,-277

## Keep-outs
Keep-Out Layer:
  lines w8: 1354,-198.26 ccw(c1432.74,-198.26) 1432.74,-277 3046.91,-277 ccw(c3046.91,-198.26) 3125.65,-198.26 3125.65,1196.35 ccw(c3084,1196.35) 3084,1238 2984,1238 cw(c3011.5,1265.5) 2984,1293 3084,1293 ccw(c3084,1334.65) 3125.65,1334.65 3125.65,3578.75 3125.65,3598.12 ccw(c3075.65,3598.12) 3075.65,3648.12 3046.91,3648.12 1432.74,3648.12 1404,3648.12 ccw(c1404,3598.12) 1354,3598.12 1354,3582.09 1354,1338 ccw(c1397.75,1336.75) 1396.5,1293 1496.5,1293 cw(c1469,1265.5) 1496.5,1238 1396.5,1238 ccw(c1397.75,1194.25) 1354,1193 1354,-198.26 ; 1569,1238 cw(c1596.5,1265.5) 1569,1293 1919,1293 1939,1293 cw(c1911.5,1265.5) 1939,1238 1919,1238 1569,1238 ; 2614,1238 cw(c2641.5,1265.5) 2614,1293 2634,1293 2914,1293 cw(c2886.5,1265.5) 2914,1238 2634,1238 2614,1238

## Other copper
Top Layer:
  region net 3.3V_OUT: 1759,3150 1814,3150 1820,3144 1820,3088 1810,3078 1761,3078 1752,3087 1752,3143
  pour cut-out: 3009,1093 3019,1093 3019,1083 3009,1083
  pour cut-out: 1629,213 1639,213 1639,203 1629,203
  pour cut-out: 1629,248 1639,248 1639,238 1629,238
  pour cut-out: 1684,248 1689.5,248 1689.5,226 1684,226
  pour cut-out: 1684,213 1694,213 1694,203 1684,203
  region net 5V_USB_CHGR: 1739,-42 1749,-32 1774,-32 1819,-77 1864,-77 1884,-97 2014,-97 2014,-157 1869,-157 1869,-137 1844,-112 1789,-112 1754,-77 1739,-62
  region net 3V3_PYLK: 1594,38 1644,38 1664,18 1709,18 1714,13 1714,-27 1699,-42 1699,-112 1716.5,-129.5 1709,-137 1647.39,-137 1647.39,-123.51 1659,-111.9 1659,-47 1634,-22 1594,-22
  region net 3V3_PYLK: 2449,-122 2459,-112 2479,-112 2489,-122 2489,-147 2494,-152 2539,-152 2544,-157 2544,-172 2539,-177 2484,-177 2449,-142
  region net 3V3_USB_PYLK: 2581.5,-157 2654,-157 2669,-142 2689,-142 2699,-152 2699,-172 2684,-187 2669,-187 2644,-212 2644,-252 2579,-252 2579,-158.67
  pour cut-out: 1744,218 1754,218 1754,208 1744,208
  pour cut-out: 1799,218 1809,218 1809,208 1799,208
  pour cut-out: 2981.43,760 2991.43,760 2991.43,750 2981.43,750
  pour cut-out: 3029,798 3039,798 3039,788 3029,788
Bottom Layer:
  region net 3.3V_OUT: 1707,3019 1748,3019 1762,3005 1809,3005 1817,3013 1817,3191 1806,3202 1770,3202 1755,3187 1755,3067 1739,3051 1705,3051 1695,3041 1695,3031
  region net NetC38_2: 1876,3126 1876,3151 1881,3156 1957,3156 2010,3209 2066,3209 2066,3153 2017,3153 1958,3094 1958,3018 1954,3014 1904,3014 1890,3000 1840,3000 1840,3058 1847,3065 1919,3065 1919,3115 1912,3122 1880,3122

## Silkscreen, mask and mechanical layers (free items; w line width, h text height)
Top Overlay:
  drawing of 1057 lines, arcs and shapes, not listed
  text "USER_PB0" at 1449,3288.66 h60
  text "NRST" at 2819,3288.64 h60
  text "VDD*" at 2207,3120 h50
  text "5V" at 2334,3119.54 h50
  text "3V3" at 2106,3117.54 h50
  text "33" at 1405,3080.54 h50
  text "34" at 1508,3080.54 h50
  text "31" at 3043,3079.54 h50
  text "32" at 2942,3077.54 h50
  text "VDD_SEL" at 1900,3059.89 h50
  text "VDD" at 2661,3003.19 h55
  text "GND" at 2777.41,3002.59 h55
  text "B13" at 1731.35,3001.58 h55
  text "B12" at 1596,3001 h55
  text "PY32F040_EP-START V2.0" at 1993,2948.6 h65
  text "B11" at 2682,2903.8 h55
  text "B10" at 2799.91,2902.6 h55
  text "B14" at 1596,2901.4 h55
  text "B15" at 1731.08,2901.31 h55
  text "2025-06" at 2098.95,2843.47 h65
  text "B2" at 2682,2804.41 h55
  text "B1" at 2833.87,2803.2 h55
  text "C6" at 1596,2800.75 h55
  text "C7" at 1744.77,2800.51 h55
  text "B0" at 2689,2703.59 h55
  text "C5" at 2822.93,2702.73 h55
  text "C8" at 1596,2700.09 h55
  text "C9" at 1744.7,2699.7 h55
  text "C4" at 2682,2603.99 h55
  text "A7" at 2823.42,2603.45 h55
  text "A8" at 1595.96,2599.91 h55
  text "A9" at 1744.91,2599.38 h55
  text "A6" at 2681.96,2504.01 h55
  text "A5" at 2823.14,2503.6 h55
  text "A10" at 1595.96,2499.73 h55
  text "A11" at 1734.47,2499.63 h55
  text "A4" at 2681.96,2404.75 h55
  text "F4" at 2830.39,2404.32 h55
  text "A12" at 1595.96,2400.13 h55
  text "A13" at 1727.68,2399.21 h55
  text "F3" at 2682,2304.67 h55
  text "A3" at 2823.42,2304.24 h55
  text "F5" at 1596,2300.09 h55
  text "F6" at 1754,2298.59 h55
  text "A2" at 2681.96,2205.33 h55
  text "A1" at 2830.2,2204.88 h55
  text "A14" at 1595.96,2200.49 h55
  text "A15" at 1727.4,2198.62 h55
  text "A0" at 2660.96,2105.36 h55
  text "VCCA" at 2745,2104.42 h55
  text "C10" at 1596,2099.83 h55
  text "C11" at 1734.25,2097.81 h55
  text "VSSA" at 2661,2004.91 h55
  text "C3" at 2823.21,2003.85 h55
  text "C12" at 1596,1999.17 h55
  text "F7" at 1749.83,1998.19 h55
  text "C2" at 2681,1904.45 h55
  text "C1" at 2829.99,1903.43 h55
  text "B3" at 1596,1898.89 h55
  text "B4" at 1746.79,1898.58 h55
  text "C0" at 2681,1803.99 h55
  text "F2" at 2830.62,1804.02 h55
  text "B5" at 1596,1798.89 h55
  text "B6" at 1746.66,1798.26 h55
  text "F1" at 2685,1705 h55
  text "F0" at 2830.39,1704.04 h55
  text "B7" at 1596,1699.42 h55
  text "F8" at 1749.76,1697.94 h55
  text "C15" at 2672,1604.15 h55
  text "C14" at 2796.03,1603.57 h55
  text "B8" at 1596,1599.25 h55
  text "B9" at 1746.58,1597.62 h55
  text "C13" at 2672,1503.59 h55
  text "F9" at 2830.19,1503.59 h55
  text "GND" at 1596,1498.59 h55
  text "VDD" at 1712,1498 h55
  text "NRST" at 2088.41,1431 h55 r90
  text "SWC" at 2189.71,1431 h55 r90
  text "GND" at 2291.01,1431 h55 r90
  text "SWD" at 2392.31,1431 h55 r90
  text "VDD*" at 2493,1431 h55 r90
  text "2" at 2947.96,1422 h50
  text "1" at 3050,1422 h50
  text "64" at 1502,1420.54 h50
  text "63" at 1404,1420.49 h50
  text "BOOT0" at 1707,1406.22 h45
  text "GND" at 1587,1402.98 h50
  text "VDD*" at 1871,1403 h50
  text "VDD*" at 2621,1402.51 h45
  text "VDD" at 2730,1402.51 h45
  text "IDD" at 2822,1342 h45
  text "BOOT_SEL" at 1431,1325.1 h40
  text "NRST" at 2004,1171.48 h45
  text "SWC" at 2127.88,1171.48 h45
  text "GND" at 2236.55,1171.48 h45
  text "SWD" at 2339.91,1171.48 h45
  text "VDD*" at 2448,1171 h45
  text "SWO" at 1996,899.47 h55
  text "RTS" at 2129,899.47 h55
  text "DTR" at 2234,898.88 h55
  text "TX" at 2350.31,898.88 h55
  text "RX" at 2444,898.88 h55
  text "5V" at 1544,798.64 h60
  text "3V3" at 1764,798.64 h60
  text "VDD*" at 1619,798 h60
  text "BT0" at 2489.46,137 h50 r90
  text "VDD" at 2587.9,137 h50 r90
  text "DIO" at 2687.42,137 h50 r90
  text "GND" at 2786.94,137 h50 r90
  text "CLK" at 2886.46,137 h50 r90
  text "PY-LINK V2.0" at 2051.04,120.23 h65
Bottom Overlay:
Mechanical 1:
  lines w6: 1569,1238 1919,1238 1939,1238 ; 1569,1293 1919,1293 1939,1293 ; 2614,1238 2634,1238 2914,1238 ; 2614,1293 2634,1293 2914,1293
  lines w8: 1569,1238 cw(c1596.5,1265.5) 1569,1293 ; 1939,1238 ccw(c1911.5,1265.5) 1939,1293 ; 2614,1238 cw(c2641.5,1265.5) 2614,1293 ; 2914,1238 ccw(c2886.5,1265.5) 2914,1293

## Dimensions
1396.5,1293 to 1432.74,3648.12 on Mechanical 1
3124,-277 to 3190,3649 on Mechanical 1
1432.74,-277 to 1349,1228 on Mechanical 1
1354,-277 to 3124,-337 on Mechanical 1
